VERSION 5.7 ;
  NOWIREEXTENSIONATPIN ON ;
  DIVIDERCHAR "/" ;
  BUSBITCHARS "[]" ;
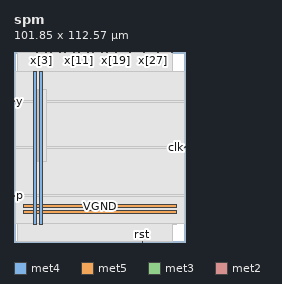
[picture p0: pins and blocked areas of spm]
MACRO spm
  CLASS BLOCK ;
  FOREIGN spm ;
  ORIGIN 0.000 0.000 ;
  SIZE 101.850 BY 112.570 ;
  PIN VGND
    DIRECTION INOUT ;
    USE GROUND ;
    PORT
      LAYER met4 ;
        RECT 15.020 10.640 16.620 100.880 ;
    END
    PORT
      LAYER met5 ;
        RECT 5.520 20.380 96.140 21.980 ;
    END
  END VGND
  PIN VPWR
    DIRECTION INOUT ;
    USE POWER ;
    PORT
      LAYER met4 ;
        RECT 11.720 10.640 13.320 100.880 ;
    END
    PORT
      LAYER met5 ;
        RECT 5.520 17.080 96.140 18.680 ;
    END
  END VPWR
  PIN clk
    DIRECTION INPUT ;
    USE SIGNAL ;
    ANTENNAGATEAREA 0.852000 ;
    PORT
      LAYER met3 ;
        RECT 101.250 55.800 101.850 56.400 ;
    END
  END clk
  PIN p
    DIRECTION OUTPUT ;
    USE SIGNAL ;
    ANTENNADIFFAREA 0.702900 ;
    PORT
      LAYER met3 ;
        RECT 0.000 27.240 0.600 27.840 ;
    END
  END p
  PIN rst
    DIRECTION INPUT ;
    USE SIGNAL ;
    ANTENNAGATEAREA 0.213000 ;
    PORT
      LAYER met2 ;
        RECT 75.990 0.000 76.270 0.280 ;
    END
  END rst
  PIN x[0]
    DIRECTION INPUT ;
    USE SIGNAL ;
    ANTENNAGATEAREA 0.213000 ;
    PORT
      LAYER met2 ;
        RECT 7.910 112.290 8.190 112.570 ;
    END
  END x[0]
  PIN x[10]
    DIRECTION INPUT ;
    USE SIGNAL ;
    ANTENNAGATEAREA 0.213000 ;
    PORT
      LAYER met2 ;
        RECT 35.510 112.290 35.790 112.570 ;
    END
  END x[10]
  PIN x[11]
    DIRECTION INPUT ;
    USE SIGNAL ;
    ANTENNAGATEAREA 0.213000 ;
    PORT
      LAYER met2 ;
        RECT 38.270 112.290 38.550 112.570 ;
    END
  END x[11]
  PIN x[12]
    DIRECTION INPUT ;
    USE SIGNAL ;
    ANTENNAGATEAREA 0.213000 ;
    PORT
      LAYER met2 ;
        RECT 41.030 112.290 41.310 112.570 ;
    END
  END x[12]
  PIN x[13]
    DIRECTION INPUT ;
    USE SIGNAL ;
    ANTENNAGATEAREA 0.213000 ;
    PORT
      LAYER met2 ;
        RECT 43.790 112.290 44.070 112.570 ;
    END
  END x[13]
  PIN x[14]
    DIRECTION INPUT ;
    USE SIGNAL ;
    ANTENNAGATEAREA 0.213000 ;
    PORT
      LAYER met2 ;
        RECT 46.550 112.290 46.830 112.570 ;
    END
  END x[14]
  PIN x[15]
    DIRECTION INPUT ;
    USE SIGNAL ;
    ANTENNAGATEAREA 0.213000 ;
    PORT
      LAYER met2 ;
        RECT 49.310 112.290 49.590 112.570 ;
    END
  END x[15]
  PIN x[16]
    DIRECTION INPUT ;
    USE SIGNAL ;
    ANTENNAGATEAREA 0.213000 ;
    PORT
      LAYER met2 ;
        RECT 52.070 112.290 52.350 112.570 ;
    END
  END x[16]
  PIN x[17]
    DIRECTION INPUT ;
    USE SIGNAL ;
    ANTENNAGATEAREA 0.213000 ;
    PORT
      LAYER met2 ;
        RECT 54.830 112.290 55.110 112.570 ;
    END
  END x[17]
  PIN x[18]
    DIRECTION INPUT ;
    USE SIGNAL ;
    ANTENNAGATEAREA 0.213000 ;
    PORT
      LAYER met2 ;
        RECT 57.590 112.290 57.870 112.570 ;
    END
  END x[18]
  PIN x[19]
    DIRECTION INPUT ;
    USE SIGNAL ;
    ANTENNAGATEAREA 0.213000 ;
    PORT
      LAYER met2 ;
        RECT 60.350 112.290 60.630 112.570 ;
    END
  END x[19]
  PIN x[1]
    DIRECTION INPUT ;
    USE SIGNAL ;
    ANTENNAGATEAREA 0.213000 ;
    PORT
      LAYER met2 ;
        RECT 10.670 112.290 10.950 112.570 ;
    END
  END x[1]
  PIN x[20]
    DIRECTION INPUT ;
    USE SIGNAL ;
    ANTENNAGATEAREA 0.213000 ;
    PORT
      LAYER met2 ;
        RECT 63.110 112.290 63.390 112.570 ;
    END
  END x[20]
  PIN x[21]
    DIRECTION INPUT ;
    USE SIGNAL ;
    ANTENNAGATEAREA 0.213000 ;
    PORT
      LAYER met2 ;
        RECT 65.870 112.290 66.150 112.570 ;
    END
  END x[21]
  PIN x[22]
    DIRECTION INPUT ;
    USE SIGNAL ;
    ANTENNAGATEAREA 0.213000 ;
    PORT
      LAYER met2 ;
        RECT 68.630 112.290 68.910 112.570 ;
    END
  END x[22]
  PIN x[23]
    DIRECTION INPUT ;
    USE SIGNAL ;
    ANTENNAGATEAREA 0.213000 ;
    PORT
      LAYER met2 ;
        RECT 71.390 112.290 71.670 112.570 ;
    END
  END x[23]
  PIN x[24]
    DIRECTION INPUT ;
    USE SIGNAL ;
    ANTENNAGATEAREA 0.213000 ;
    PORT
      LAYER met2 ;
        RECT 74.150 112.290 74.430 112.570 ;
    END
  END x[24]
  PIN x[25]
    DIRECTION INPUT ;
    USE SIGNAL ;
    ANTENNAGATEAREA 0.213000 ;
    PORT
      LAYER met2 ;
        RECT 76.910 112.290 77.190 112.570 ;
    END
  END x[25]
  PIN x[26]
    DIRECTION INPUT ;
    USE SIGNAL ;
    ANTENNAGATEAREA 0.213000 ;
    PORT
      LAYER met2 ;
        RECT 79.670 112.290 79.950 112.570 ;
    END
  END x[26]
  PIN x[27]
    DIRECTION INPUT ;
    USE SIGNAL ;
    ANTENNAGATEAREA 0.213000 ;
    PORT
      LAYER met2 ;
        RECT 82.430 112.290 82.710 112.570 ;
    END
  END x[27]
  PIN x[28]
    DIRECTION INPUT ;
    USE SIGNAL ;
    ANTENNAGATEAREA 0.213000 ;
    PORT
      LAYER met2 ;
        RECT 85.190 112.290 85.470 112.570 ;
    END
  END x[28]
  PIN x[29]
    DIRECTION INPUT ;
    USE SIGNAL ;
    ANTENNAGATEAREA 0.213000 ;
    PORT
      LAYER met2 ;
        RECT 87.950 112.290 88.230 112.570 ;
    END
  END x[29]
  PIN x[2]
    DIRECTION INPUT ;
    USE SIGNAL ;
    ANTENNAGATEAREA 0.213000 ;
    PORT
      LAYER met2 ;
        RECT 13.430 112.290 13.710 112.570 ;
    END
  END x[2]
  PIN x[30]
    DIRECTION INPUT ;
    USE SIGNAL ;
    ANTENNAGATEAREA 0.213000 ;
    PORT
      LAYER met2 ;
        RECT 90.710 112.290 90.990 112.570 ;
    END
  END x[30]
  PIN x[31]
    DIRECTION INPUT ;
    USE SIGNAL ;
    ANTENNAGATEAREA 0.213000 ;
    PORT
      LAYER met2 ;
        RECT 93.470 112.290 93.750 112.570 ;
    END
  END x[31]
  PIN x[3]
    DIRECTION INPUT ;
    USE SIGNAL ;
    ANTENNAGATEAREA 0.213000 ;
    PORT
      LAYER met2 ;
        RECT 16.190 112.290 16.470 112.570 ;
    END
  END x[3]
  PIN x[4]
    DIRECTION INPUT ;
    USE SIGNAL ;
    ANTENNAGATEAREA 0.213000 ;
    PORT
      LAYER met2 ;
        RECT 18.950 112.290 19.230 112.570 ;
    END
  END x[4]
  PIN x[5]
    DIRECTION INPUT ;
    USE SIGNAL ;
    ANTENNAGATEAREA 0.213000 ;
    PORT
      LAYER met2 ;
        RECT 21.710 112.290 21.990 112.570 ;
    END
  END x[5]
  PIN x[6]
    DIRECTION INPUT ;
    USE SIGNAL ;
    ANTENNAGATEAREA 0.213000 ;
    PORT
      LAYER met2 ;
        RECT 24.470 112.290 24.750 112.570 ;
    END
  END x[6]
  PIN x[7]
    DIRECTION INPUT ;
    USE SIGNAL ;
    ANTENNAGATEAREA 0.213000 ;
    PORT
      LAYER met2 ;
        RECT 27.230 112.290 27.510 112.570 ;
    END
  END x[7]
  PIN x[8]
    DIRECTION INPUT ;
    USE SIGNAL ;
    ANTENNAGATEAREA 0.213000 ;
    PORT
      LAYER met2 ;
        RECT 29.990 112.290 30.270 112.570 ;
    END
  END x[8]
  PIN x[9]
    DIRECTION INPUT ;
    USE SIGNAL ;
    ANTENNAGATEAREA 0.213000 ;
    PORT
      LAYER met2 ;
        RECT 32.750 112.290 33.030 112.570 ;
    END
  END x[9]
  PIN y
    DIRECTION INPUT ;
    USE SIGNAL ;
    ANTENNAGATEAREA 0.213000 ;
    PORT
      LAYER met3 ;
        RECT 0.000 83.000 0.600 83.600 ;
    END
  END y
  OBS
      LAYER nwell ;
        RECT 5.330 10.795 96.330 100.830 ;
      LAYER li1 ;
        RECT 5.520 10.795 96.140 100.725 ;
      LAYER met1 ;
        RECT 1.910 10.640 96.140 100.880 ;
      LAYER met2 ;
        RECT 1.930 112.010 7.630 112.500 ;
        RECT 8.470 112.010 10.390 112.500 ;
        RECT 11.230 112.010 13.150 112.500 ;
        RECT 13.990 112.010 15.910 112.500 ;
        RECT 16.750 112.010 18.670 112.500 ;
        RECT 19.510 112.010 21.430 112.500 ;
        RECT 22.270 112.010 24.190 112.500 ;
        RECT 25.030 112.010 26.950 112.500 ;
        RECT 27.790 112.010 29.710 112.500 ;
        RECT 30.550 112.010 32.470 112.500 ;
        RECT 33.310 112.010 35.230 112.500 ;
        RECT 36.070 112.010 37.990 112.500 ;
        RECT 38.830 112.010 40.750 112.500 ;
        RECT 41.590 112.010 43.510 112.500 ;
        RECT 44.350 112.010 46.270 112.500 ;
        RECT 47.110 112.010 49.030 112.500 ;
        RECT 49.870 112.010 51.790 112.500 ;
        RECT 52.630 112.010 54.550 112.500 ;
        RECT 55.390 112.010 57.310 112.500 ;
        RECT 58.150 112.010 60.070 112.500 ;
        RECT 60.910 112.010 62.830 112.500 ;
        RECT 63.670 112.010 65.590 112.500 ;
        RECT 66.430 112.010 68.350 112.500 ;
        RECT 69.190 112.010 71.110 112.500 ;
        RECT 71.950 112.010 73.870 112.500 ;
        RECT 74.710 112.010 76.630 112.500 ;
        RECT 77.470 112.010 79.390 112.500 ;
        RECT 80.230 112.010 82.150 112.500 ;
        RECT 82.990 112.010 84.910 112.500 ;
        RECT 85.750 112.010 87.670 112.500 ;
        RECT 88.510 112.010 90.430 112.500 ;
        RECT 91.270 112.010 93.190 112.500 ;
        RECT 94.030 112.010 94.200 112.500 ;
        RECT 1.930 0.560 94.200 112.010 ;
        RECT 1.930 0.280 75.710 0.560 ;
        RECT 76.550 0.280 94.200 0.560 ;
      LAYER met3 ;
        RECT 0.600 84.000 101.250 100.805 ;
        RECT 1.000 82.600 101.250 84.000 ;
        RECT 0.600 56.800 101.250 82.600 ;
        RECT 0.600 55.400 100.850 56.800 ;
        RECT 0.600 28.240 101.250 55.400 ;
        RECT 1.000 26.840 101.250 28.240 ;
        RECT 0.600 10.715 101.250 26.840 ;
      LAYER met4 ;
        RECT 14.095 47.775 14.620 90.265 ;
        RECT 17.020 47.775 19.025 90.265 ;
  END
END spm
END LIBRARY

